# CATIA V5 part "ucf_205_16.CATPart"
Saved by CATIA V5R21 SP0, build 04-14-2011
Part number: ucf_205_16
Bounding box of the stored display mesh (mm): x 5.975 to 13.525, y -3.969 to 3.969, z -20.662 to -13.113
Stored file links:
  C:\TPO v2\SharedFS\Outgoing\ucf_205_16.CATPart

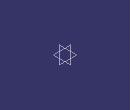
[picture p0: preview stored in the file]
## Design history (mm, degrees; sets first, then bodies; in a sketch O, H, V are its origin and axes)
AxisSystem1: origin (0, 0, 0), X (1, 0, 0), Y (0, 1, 0), Z (0, 0, 1)
Body1 "ucf_205_16" (main body)
  Solid1: solid without history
